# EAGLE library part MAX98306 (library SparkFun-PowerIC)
Stereo 3.7W Class D Amplifier Datasheet: http://datasheets.maxim-ic.com/en/ds/MAX98306.pdf The MAX98306 stereo 3.7W Class D amplifier provides Class AB audio performance with Class D efficiency. This device offers five selectable gain settings (6dB, 9dB, 12dB, 15dB, and 18dB) set by a single gain-select input (GAIN). Active emissions limiting, edge-rate, and overshoot control circuitry combined with a filterless spread-spectrum modulation scheme (SSM) provide excellent EMI performance while eliminating the need for output filtering found in traditional Class D devices. These features reduce application component count. The IC's 2.0mA quiescent current with a 3.7V supply extends battery life in portable applications. The IC is available in a 14-pin TDFN (3mm x 3mm x 0.75mm) package specified over the extended -40NC to +85NC temperature range.

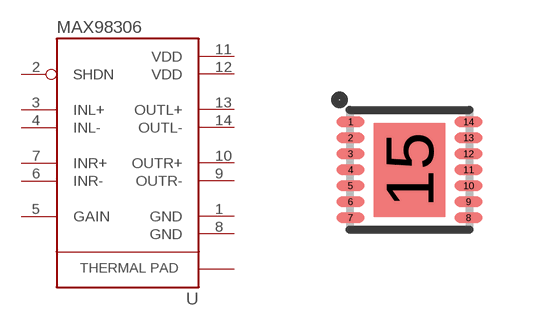
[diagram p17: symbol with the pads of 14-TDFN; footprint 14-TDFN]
Designator prefix U

## MAX98306ETD+  [14-TDFN]
1  GND  pwr
2  SHDN  in
3  INL+
4  INL-
5  GAIN  pas
6  INR-
7  INR+
8  GND  pwr
9  OUTR-
10  OUTR+
11  VDD  pwr
12  VDD  pwr
13  OUTL+
14  OUTL-
15  GND  pwr

## Footprint 14-TDFN (pad centres in mm)
smd 0.7 x 0.25: 1 -1.475,1.2; 2 -1.475,0.8; 3 -1.475,0.4; 4 -1.475,0; 5 -1.475,-0.4; 6 -1.475,-0.8; 7 -1.475,-1.2; 8 1.475,-1.2; 9 1.475,-0.8; 10 1.475,-0.4; 11 1.475,0; 12 1.475,0.4; 13 1.475,0.8; 14 1.475,1.2
smd 1.78 x 2.35: 15 0,0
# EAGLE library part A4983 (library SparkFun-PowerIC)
DMOS Microstepping Driver with Translator ---------------- 2/4/2013 - 1:1 variant has an imported .bmp image of the chip. The pads have been rounded and shifted so as to better fit this particular QFN package of this chip. The stencil layer has also been altered so that there is less paste under the IC. This is the package to use on all boards!

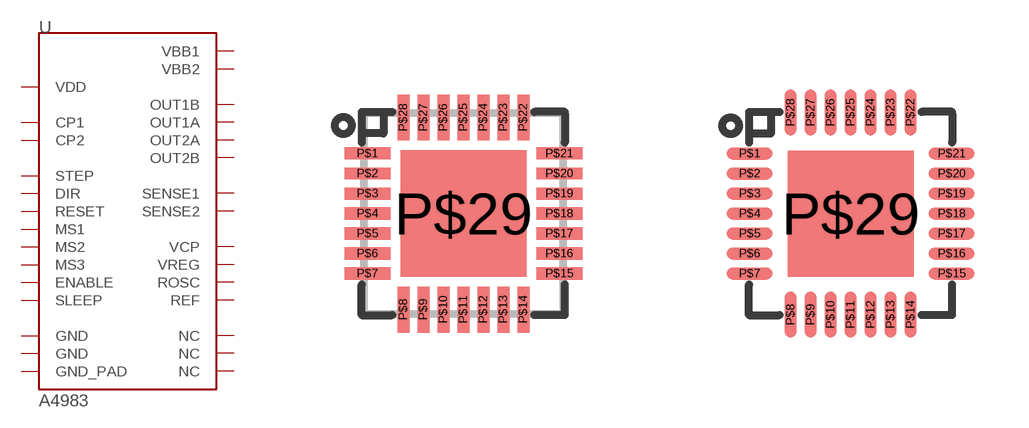
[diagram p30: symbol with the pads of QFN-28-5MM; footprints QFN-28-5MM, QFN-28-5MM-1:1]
Designator prefix U

## A4983REGULAR  [QFN-28-5MM]
P$1  OUT2B
P$2  ENABLE  in
P$3  GND  pwr
P$4  CP1
P$5  CP2
P$6  VCP
P$7  NC  nc
P$8  VREG
P$9  MS1  in
P$10  MS2  in
P$11  MS3  in
P$12  RESET  in
P$13  ROSC
P$14  SLEEP  in
P$15  VDD  pwr
P$16  STEP  in
P$17  REF
P$18  GND  pwr
P$19  DIR  in
P$20  NC  nc
P$21  OUT1B
P$22  VBB1
P$23  SENSE1
P$24  OUT1A
P$25  NC  nc
P$26  OUT2A
P$27  SENSE2
P$28  VBB2
P$29  GND_PAD  pwr

## A49831:1  [QFN-28-5MM-1:1]
Pads as for QFN-28-5MM

## Footprint QFN-28-5MM (pad centres in mm)
smd 1.15 x 0.3: P$1 -2.4,1.5; P$2 -2.4,1; P$3 -2.4,0.5; P$4 -2.4,0; P$5 -2.4,-0.5; P$6 -2.4,-1; P$7 -2.4,-1.5; P$15 2.4,-1.5; P$16 2.4,-1; P$17 2.4,-0.5; P$18 2.4,0; P$19 2.4,0.5; P$20 2.4,1; P$21 2.4,1.5
smd 0.3 x 1.15: P$8 -1.5,-2.4; P$9 -1,-2.4; P$10 -0.5,-2.4; P$11 0,-2.4; P$12 0.5,-2.4; P$13 1,-2.4; P$14 1.5,-2.4; P$22 1.5,2.4; P$23 1,2.4; P$24 0.5,2.4; P$25 0,2.4; P$26 -0.5,2.4; P$27 -1,2.4; P$28 -1.5,2.4
smd 3.15 x 3.15: P$29 0,0

## Footprint QFN-28-5MM-1:1 (pad centres in mm)
smd 1.15 x 0.3: P$1 -2.527,1.5; P$2 -2.527,1; P$3 -2.527,0.5; P$4 -2.527,0; P$5 -2.527,-0.5; P$6 -2.527,-1; P$7 -2.527,-1.5; P$15 2.527,-1.5; P$16 2.527,-1; P$17 2.527,-0.5; P$18 2.527,0; P$19 2.527,0.5; P$20 2.527,1; P$21 2.527,1.5
smd 0.3 x 1.15: P$8 -1.5,-2.527; P$9 -1,-2.527; P$10 -0.5,-2.527; P$11 0,-2.527; P$12 0.5,-2.527; P$13 1,-2.527; P$14 1.5,-2.527; P$22 1.5,2.527; P$23 1,2.527; P$24 0.5,2.527; P$25 0,2.527; P$26 -0.5,2.527; P$27 -1,2.527; P$28 -1.5,2.527
smd 3.15 x 3.15: P$29 0,0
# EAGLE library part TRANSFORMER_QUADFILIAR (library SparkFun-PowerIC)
Transformer with 4 independent windings

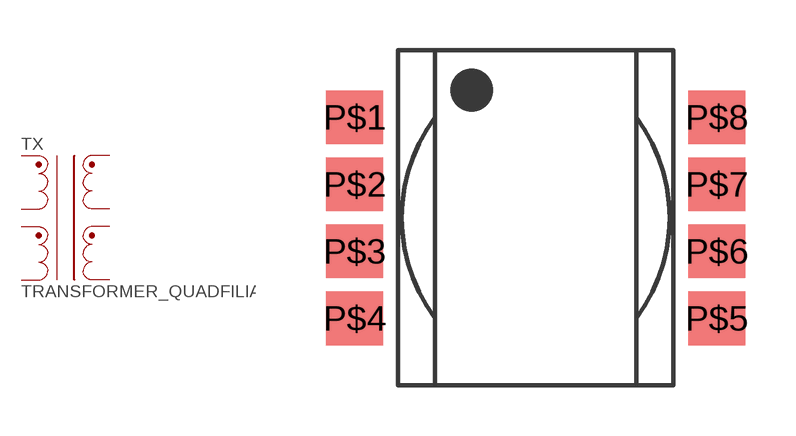
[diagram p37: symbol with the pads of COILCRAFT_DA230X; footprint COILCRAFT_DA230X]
Designator prefix TX

## TRANSFORMER_QUADFILIAR  [COILCRAFT_DA230X]
P$1  1  pas
P$2  2  pas
P$3  3  pas
P$4  4  pas
P$5  5  pas
P$6  6  pas
P$7  7  pas
P$8  8  pas

## Footprint COILCRAFT_DA230X (pad centres in mm)
Coilcraft DA2303, DA2304
smd 1.7 x 1.6: P$1 -5.4,3; P$2 -5.4,1; P$3 -5.4,-1; P$4 -5.4,-3; P$5 5.4,-3; P$6 5.4,-1; P$7 5.4,1; P$8 5.4,3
